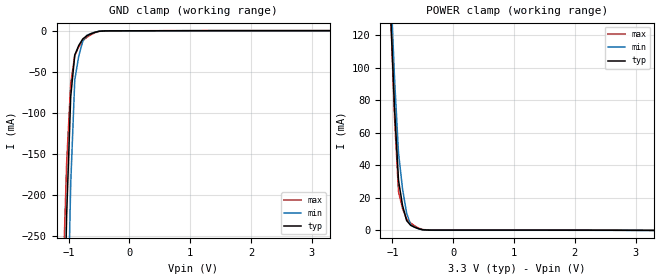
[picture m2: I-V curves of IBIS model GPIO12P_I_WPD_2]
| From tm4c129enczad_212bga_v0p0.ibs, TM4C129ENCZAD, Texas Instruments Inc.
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|   Model Cell GPIO12P_I_WPD_2
[Model]   GPIO12P_I_WPD_2
Model_type   Input
Polarity   Non-Inverting
Vinl =  0.8
Vinh =  2
C_comp   6.029616p   5.226915p   6.778838p
[Model Spec]
Vinl   0.8   0.8   0.8
Vinh   2   2   2
[Temperature Range]   25   125   -40
[Voltage Range]   3.3   2.97   3.63
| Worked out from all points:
|   GND clamp passes 1 mA (typ) near -0.52 V on its own axis
|   POWER clamp passes 1 mA (typ) near -0.57 V on its own axis
| Nom Voltages:
|   IBIASFET=3.3, VDDC=1.2, VDD=3.3, GND=0
| Min Voltages:
|   IBIASFET=2.97, VDDC=1.08, VDD=2.97, GND=0
| Max Voltages:
|   IBIASFET=3.63, VDDC=1.32, VDD=3.63, GND=0
[POWER_clamp]
|   voltage   I(typ)   I(min)   I(max)
-3.3V     3.668A     4.187A     4.057A
-1.033V   137.2mA    154.8mA    137.3mA
-966.7mV  76.04mA    94.43mA    70.11mA
-900mV    30.72mA    47.62mA    23.8mA
-833.3mV  15.25mA    25.33mA    13.39mA
-766.7mV  6.054mA    10.63mA    6.967mA
-700mV    3.122mA    3.505mA    4.521mA
-566.7mV  992.4uA    930.8uA    1.406mA
-500mV    375.5uA    371.7uA    514.2uA
-366.7mV  172.2uA    108.8uA    285.5uA
3.3V      -147.2pA   -44.58uA   78.8uA
[GND_clamp]
|   voltage   I(typ)   I(min)   I(max)
-3.3V     -18.01A    -17.27A    -18.6A
-1.1V     -459.9mA   -734.3mA   -318.7mA
-1.033V   -223.6mA   -411.6mA   -160.4mA
-966.7mV  -80.11mA   -186.8mA   -64.21mA
-900mV    -29.5mA    -59.8mA    -30.1mA
-833.3mV  -17.66mA   -30.4mA    -19.41mA
-766.7mV  -9.793mA   -12.29mA   -11.98mA
-700mV    -5.915mA   -5.456mA   -7.808mA
-500mV    -561.2uA   -614.3uA   -671.8uA
-366.7mV  -86.04uA   -85.03uA   -117.5uA
3.3V      162.1uA    89.86uA    277.3uA
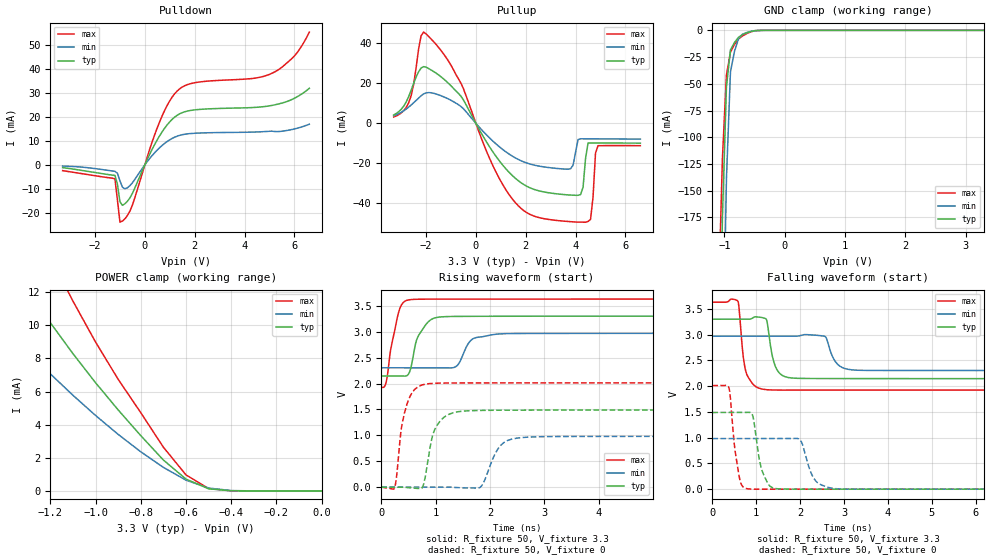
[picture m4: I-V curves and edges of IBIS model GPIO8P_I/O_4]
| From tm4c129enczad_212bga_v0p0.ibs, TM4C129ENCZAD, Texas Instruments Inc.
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|   Model Cell GPIO8P_I/O_4
[Model]   GPIO8P_I/O_4
Model_type   I/O
Polarity   Non-Inverting
Enable   Active-Low
Vinl =  0.8
Vinh =  2
Cref =  15.0000pF
Rref =  100.0000M
Vref =  0V
Vmeas =  1.65
C_comp   5.378567p   4.597605p   6.118031p
[Model Spec]
Vinl   0.8   0.8   0.8
Vinh   2   2   2
[Temperature Range]   25   125   -40
[Voltage Range]   3.3   2.97   3.63
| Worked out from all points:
|   slope of the pulldown table from 0 to 0.495 V, typ, clamps not added: 47.6 ohm
|   slope of the pullup table from 0 to 0.495 V, typ, clamps not added: 46.2 ohm
|   GND clamp passes 1 mA (typ) near -0.55 V on its own axis
|   POWER clamp passes 1 mA (typ) near -0.62 V on its own axis
|   rising waveform, R_fixture 50, V_fixture 3.3: 20-80 % time 215ps typ, 200ps min, 172ps max; typ from 2.15 V to 3.3 V
|   rising waveform, R_fixture 50, V_fixture 0: 20-80 % time 199ps typ, 254ps min, 174ps max; typ from 0 V to 1.49 V
|   falling waveform, R_fixture 50, V_fixture 3.3: 20-80 % time 162ps typ, 207ps min, 140ps max; typ from 3.3 V to 2.15 V
|   falling waveform, R_fixture 50, V_fixture 0: 20-80 % time 193ps typ, 242ps min, 155ps max; typ from 1.49 V to 0 V
| Nom Voltages:
|   VBAT=3.3, VDDC=1.2, VDD=3.3, GND=0
| Min Voltages:
|   VBAT=2.97, VDDC=1.08, VDD=2.97, GND=0
| Max Voltages:
|   VBAT=3.63, VDDC=1.32, VDD=3.63, GND=0
[POWER_clamp]
|   voltage   I(typ)   I(min)   I(max)
-3.3V     116.1mA    496.8mA    244.3mA
-1.533V   17.14mA    11.87mA    23.97mA
-1.3V     12.14mA    8.433mA    16.92mA
-1.267V   11.48mA    7.98mA     15.99mA
-1.133V   8.919mA    6.212mA    12.36mA
-1.1V     8.296mA    5.781mA    11.47mA
-900mV    4.896mA    3.418mA    6.747mA
-800mV    3.341mA    2.365mA    4.729mA
-700mV    1.867mA    1.423mA    2.643mA
-600mV    716.2uA    650.8uA    969.8uA
-500mV    130.1uA    172.8uA    144.6uA
0V        364.7pA    9.133nA    53.42pA
[Pulldown]
|   voltage   I(typ)   I(min)   I(max)
-3.3V     -1.169mA   -506.4uA   -2.421mA
-1.2V     -4.435mA   -2.714mA   -5.871mA
-1.1V     -8.109mA   -3.531mA   -14.66mA
-1V       -15.39mA   -6.64mA    -23.94mA
-900mV    -16.88mA   -9.321mA   -23.45mA
-500mV    -11.93mA   -7.505mA   -16.83mA
600mV     12.25mA    7.223mA    18.14mA
1.3V      20.71mA    11.98mA    30.84mA
2V        22.93mA    13.18mA    34.26mA
5.1V      24.79mA    14.05mA    38.2mA
6V        27.77mA    14.98mA    45.41mA
6.6V      31.94mA    16.95mA    55.4mA
[Pullup]
|   voltage   I(typ)   I(min)   I(max)
-3.3V     4.211mA    3.769mA    3.166mA
-2.7V     13.31mA    8.095mA    10.2mA
-2.1V     28.4mA     14.72mA    45.7mA
1.1V      -21.27mA   -13.31mA   -31.15mA
2.1V      -31.88mA   -20.11mA   -45.16mA
3.8V      -35.93mA   -22.75mA   -49.25mA
4.2V      -35.67mA   -7.739mA   -49.48mA
4.5V      -9.864mA   -7.75mA    -49.16mA
4.6V      -9.858mA   -7.755mA   -48.11mA
4.8V      -9.854mA   -7.767mA   -14.84mA
4.9V      -9.854mA   -7.774mA   -11.18mA
6.6V      -9.917mA   -7.893mA   -11.16mA
[GND_clamp]
|   voltage   I(typ)   I(min)   I(max)
-3.3V     -16.39A    -15.37A    -17.22A
-1.1V     -384.9mA   -635.5mA   -255.1mA
-1.033V   -175.3mA   -338.1mA   -120.1mA
-966.7mV  -53.11mA   -139.3mA   -41.82mA
-900mV    -18.35mA   -38.91mA   -20.36mA
-833.3mV  -11.36mA   -19.64mA   -13.17mA
-766.7mV  -6.568mA   -7.874mA   -8.128mA
-700mV    -3.981mA   -3.622mA   -5.248mA
-500mV    -326.7uA   -386.2uA   -372.4uA
-366.7mV  -15.8uA    -32.57uA   -14.68uA
3.3V      364.7pA    3.701uA    29.32pA
[Ramp]
| variable   typ   min   max
dV/dt_f 0.72052864/0.1623651n 0.41850119/0.20981261n   1.060543/0.1399875n
dV/dt_r  0.9119039/0.2000912n 0.60163088/0.25774668n  1.2306796/0.17446536n
R_load = 50
[Rising Waveform]
R_fixture = 50
V_fixture = 3.3
V_fixture_min = 2.97
V_fixture_max = 3.63
|   time   V(typ)   V(min)   V(max)
0s        2.146V     2.304V     1.925V
85.7ps    2.146V     2.304V     2.011V
342.6ps   2.146V     2.304V     3.454V
578.5ps   2.48V      2.304V     3.624V
818.7ps   3.137V     2.304V     3.628V
1.149ns   3.289V     2.304V     3.629V
1.4ns     3.295V     2.352V     3.629V
1.694ns   3.297V     2.868V     3.63V
2.273ns   3.299V     2.962V     3.63V
20.04ns   3.3V       2.97V      3.63V
[Rising Waveform]
R_fixture = 50
V_fixture = 0
V_fixture_min = 0
V_fixture_max = 0
|   time   V(typ)   V(min)   V(max)
0s        0V         0V         0V
238.5ps   0V         0V         -25.62mV
446.3ps   -3.239mV   0V         1.513V
744.7ps   -20.72mV   0V         1.971V
880.7ps   664.9mV    0V         1.998V
1.227ns   1.399V     0V         2.01V
1.812ns   1.481V     -8.275mV   2.012V
2.193ns   1.485V     803.3mV    2.012V
2.73ns    1.487V     967.1mV    2.012V
20.01ns   1.489V     982.4mV    2.012V
[Falling Waveform]
R_fixture = 50
V_fixture = 3.3
V_fixture_min = 2.97
V_fixture_max = 3.63
|   time   V(typ)   V(min)   V(max)
0s        3.3V       2.97V      3.63V
580.2ps   3.3V       2.97V      3.651V
767.2ps   3.3V       2.97V      2.273V
1.221ns   3.306V     2.97V      1.932V
1.434ns   2.388V     2.97V      1.925V
1.802ns   2.159V     2.97V      1.924V
2.56ns    2.148V     2.969V     1.925V
2.854ns   2.148V     2.425V     1.925V
3.306ns   2.148V     2.31V      1.925V
20.04ns   2.146V     2.304V     1.925V
[Falling Waveform]
R_fixture = 50
V_fixture = 0
V_fixture_min = 0
V_fixture_max = 0
|   time   V(typ)   V(min)   V(max)
0s        1.489V     981.9mV    2.013V
377.1ps   1.489V     981.9mV    1.97V
619.7ps   1.489V     981.9mV    205.5mV
817.9ps   1.492V     981.9mV    5.58mV
1.138ns   346.6mV    981.9mV    0V
1.475ns   8.738mV    981.8mV    0V
1.986ns   0V         968.1mV    0V
2.353ns   0V         162.4mV    0V
2.841ns   0V         7.388mV    0V
20.01ns   0V         0V         0V
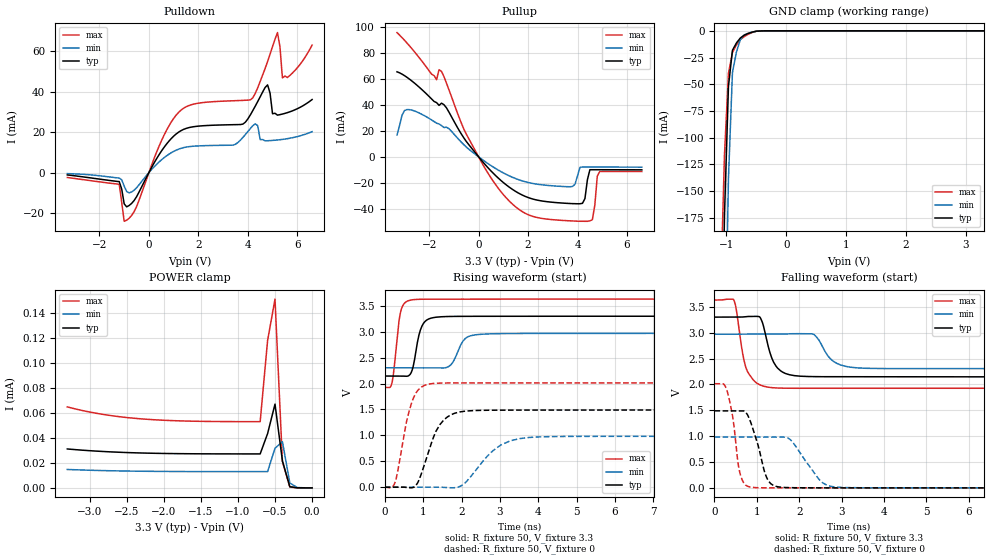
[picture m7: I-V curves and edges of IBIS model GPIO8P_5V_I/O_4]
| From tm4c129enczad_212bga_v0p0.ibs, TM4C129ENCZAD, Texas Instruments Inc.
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|   Model Cell GPIO8P_5V_I/O_4
[Model]   GPIO8P_5V_I/O_4
Model_type   I/O
Polarity   Non-Inverting
Enable   Active-Low
Vinl =  0.8
Vinh =  2
Cref =  15.0000pF
Rref =  100.0000M
Vref =  0V
Vmeas =  1.65
C_comp   7.738177p   6.063161p   9.392973p
[Model Spec]
Vinl   0.8   0.8   0.8
Vinh   2   2   2
[Temperature Range]   25   125   -40
[Voltage Range]   3.3   2.97   3.63
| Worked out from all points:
|   slope of the pulldown table from 0 to 0.495 V, typ, clamps not added: 47.6 ohm
|   slope of the pullup table from 0 to 0.495 V, typ, clamps not added: 46.2 ohm
|   GND clamp passes 1 mA (typ) near -0.55 V on its own axis
|   rising waveform, R_fixture 50, V_fixture 3.3: 20-80 % time 194ps typ, 262ps min, 148ps max; typ from 2.15 V to 3.3 V
|   rising waveform, R_fixture 50, V_fixture 0: 20-80 % time 450ps typ, 738ps min, 330ps max; typ from 0 V to 1.49 V
|   falling waveform, R_fixture 50, V_fixture 3.3: 20-80 % time 259ps typ, 342ps min, 226ps max; typ from 3.3 V to 2.15 V
|   falling waveform, R_fixture 50, V_fixture 0: 20-80 % time 299ps typ, 504ps min, 196ps max; typ from 1.49 V to 0 V
| Nom Voltages:
|   VDDC=1.2, VDD=3.3, GND=0
| Min Voltages:
|   VDDC=1.08, VDD=2.97, GND=0
| Max Voltages:
|   VDDC=1.32, VDD=3.63, GND=0
[POWER_clamp]
|   voltage   I(typ)   I(min)   I(max)
-3.3V     31.22uA    14.77uA    64.95uA
-2.8V     29.13uA    13.84uA    58.77uA
-2.3V     27.98uA    13.34uA    55.36uA
-1.7V     27.4uA     13.1uA     53.62uA
-700mV    27.24uA    13.03uA    53.12uA
-600mV    43.52uA    13.03uA    118.2uA
-500mV    67.2uA     31.8uA     151.5uA
-400mV    21.58uA    37.04uA    21.1uA
-300mV    927.4nA    3.873uA    611.4nA
-200mV    28.93nA    266.5nA    11.51nA
0V        696.9pA    10.99nA    568.3pA
[Pulldown]
|   voltage   I(typ)   I(min)   I(max)
-3.3V     -1.162mA   -505.3uA   -2.413mA
-1.2V     -4.448mA   -2.72mA    -5.833mA
-1V       -15.42mA   -6.655mA   -24.03mA
-900mV    -16.9mA    -9.327mA   -23.48mA
1.2V      19.95mA    11.56mA    29.71mA
3.4V      23.64mA    13.58mA    35.45mA
4.1V      28.41mA    21.71mA    35.87mA
4.8V      43.29mA    15.72mA    54.81mA
5V        29.04mA    15.88mA    62.21mA
5.2V      28.35mA    16.1mA     69.11mA
5.4V      28.9mA     16.38mA    46.73mA
6.6V      36.05mA    20.22mA    62.9mA
[Pullup]
|   voltage   I(typ)   I(min)   I(max)
-3.3V     65.33mA    16.73mA    95.47mA
-3V       62.41mA    35.55mA    89.6mA
-2.6V     56.73mA    35.27mA    80.83mA
-1.7V     41.66mA    25.86mA    59.29mA
-1.5V     41.23mA    23.97mA    65.63mA
200mV     -4.548mA   -2.809mA   -6.86mA
1.8V      -29.65mA   -18.67mA   -42.48mA
3.8V      -35.93mA   -22.75mA   -49.25mA
4.2V      -35.7mA    -7.761mA   -49.48mA
4.5V      -9.896mA   -7.777mA   -49.16mA
4.9V      -9.898mA   -7.805mA   -11.24mA
6.6V      -9.969mA   -7.928mA   -11.25mA
[GND_clamp]
|   voltage   I(typ)   I(min)   I(max)
-3.3V     -16.36A    -15.34A    -17.18A
-1.1V     -382.1mA   -633.4mA   -250.1mA
-1.033V   -173.3mA   -336.5mA   -116.4mA
-966.7mV  -52.02mA   -138.4mA   -39.81mA
-900mV    -18.21mA   -38.98mA   -20.34mA
-833.3mV  -11.36mA   -19.82mA   -13.17mA
-766.7mV  -6.618mA   -8.051mA   -8.134mA
-700mV    -3.983mA   -3.675mA   -5.247mA
-500mV    -328.3uA   -388.2uA   -374.5uA
-366.7mV  -15.94uA   -32.84uA   -14.83uA
3.3V      697pA      8.348uA    426.1pA
[Ramp]
| variable   typ   min   max
dV/dt_f 0.70109912/0.26037919n 0.40520664/0.34382932n  1.0338228/0.22628195n
dV/dt_r 0.90140807/0.45275695n 0.59660584/0.74446515n  1.2150245/0.33158972n
R_load = 50
[Rising Waveform]
R_fixture = 50
V_fixture = 3.3
V_fixture_min = 2.97
V_fixture_max = 3.63
|   time   V(typ)   V(min)   V(max)
0s        2.146V     2.304V     1.925V
199.6ps   2.146V     2.304V     2.057V
430.8ps   2.146V     2.304V     3.435V
774.7ps   2.456V     2.304V     3.622V
1.006ns   3.159V     2.304V     3.628V
1.421ns   3.288V     2.303V     3.629V
1.717ns   3.296V     2.359V     3.63V
2.103ns   3.298V     2.874V     3.63V
2.648ns   3.299V     2.957V     3.63V
20.14ns   3.3V       2.97V      3.63V
[Rising Waveform]
R_fixture = 50
V_fixture = 0
V_fixture_min = 0
V_fixture_max = 0
|   time   V(typ)   V(min)   V(max)
0s        0V         0V         0V
263ps     0V         0V         82.67mV
590.1ps   -7.473mV   0V         1.339V
810.6ps   32.49mV    0V         1.814V
1.231ns   887.5mV    0V         2V
1.429ns   1.201V     0V         2.009V
1.817ns   1.426V     -9.785mV   2.012V
3.021ns   1.487V     812.8mV    2.012V
3.759ns   1.489V     959.5mV    2.013V
20.01ns   1.489V     982.4mV    2.012V
[Falling Waveform]
R_fixture = 50
V_fixture = 3.3
V_fixture_min = 2.97
V_fixture_max = 3.63
|   time   V(typ)   V(min)   V(max)
0s        3.3V       2.97V      3.63V
457.4ps   3.3V       2.97V      3.628V
743.2ps   3.31V      2.97V      2.318V
1.058ns   3.308V     2.97V      1.996V
1.348ns   2.519V     2.97V      1.937V
1.677ns   2.209V     2.973V     1.926V
2.336ns   2.15V      2.97V      1.925V
2.818ns   2.148V     2.439V     1.925V
3.572ns   2.147V     2.311V     1.925V
20.14ns   2.146V     2.304V     1.925V
[Falling Waveform]
R_fixture = 50
V_fixture = 0
V_fixture_min = 0
V_fixture_max = 0
|   time   V(typ)   V(min)   V(max)
0s        1.489V     981.9mV    2.013V
279.6ps   1.489V     981.9mV    1.917V
432.1ps   1.489V     981.9mV    1.361V
601.1ps   1.489V     981.9mV    282.9mV
897ps     1.165V     981.9mV    9.076mV
1.253ns   162.1mV    981.9mV    0V
1.612ns   9.739mV    983.7mV    0V
2.499ns   0V         137.2mV    0V
2.895ns   0V         13.61mV    0V
20.01ns   0V         0V         0V
